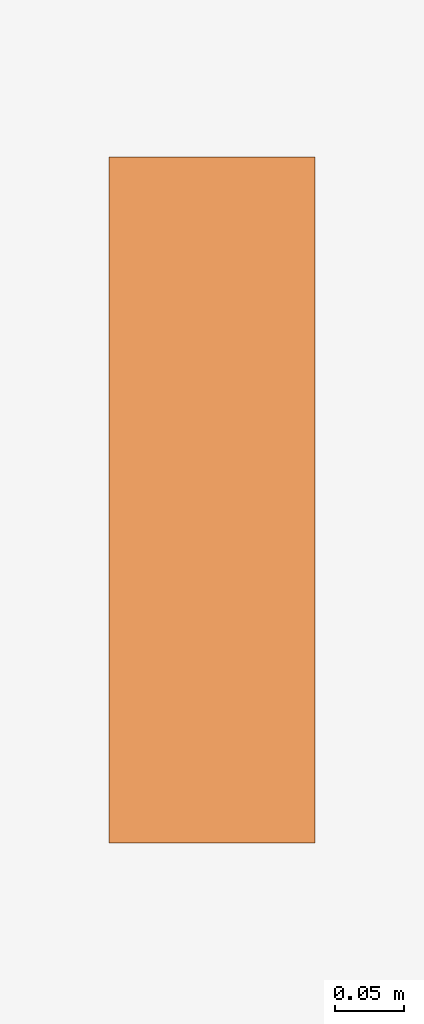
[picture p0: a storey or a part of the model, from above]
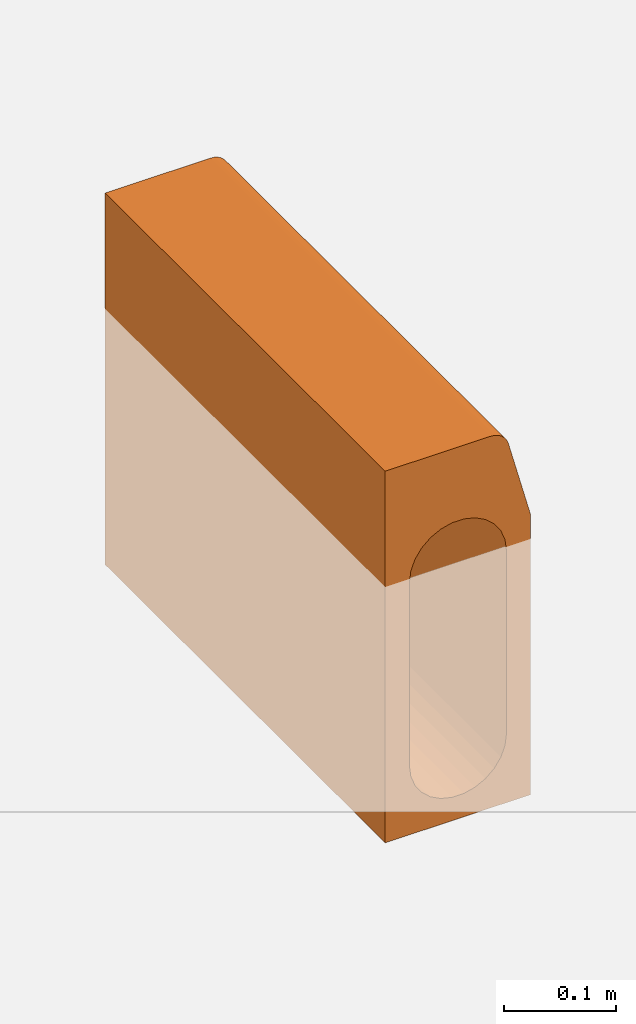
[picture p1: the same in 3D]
Properties of the parts of a building model (IFC2X3)

# File
Description: ViewDefinition [CoordinationView]
File name: 4230 - Blind unit - 500mm LG.ifc
Time: 2013-09-02T12:39:14
Written by: Autodesk Revit 2013
Made in: 20120221_2030(x64)

# IfcProject, Project Number
LongName: Project Name; Phase: Project Status

# IfcSite, Default
RefLatitude: 42, 21, 30, 344238; RefLongitude: -71, -3, -35, -194702; RefElevation: 0 mm

# IfcBuilding
Pset_BuildingCommon - NumberOfStoreys: 1
Other - Project Issue Date: Issue Date; Project Status: Project Status; Project Number: Project Number; Project Name: Project Name; Project Address: ## Street City, State Zip; Client Name: Owner

# IfcBuildingStorey, Level 1
LongName: Level 1; Elevation: 0 mm
Constraints - Elevation Base: 0; Elevation: 0 mm
Graphics - Line Pattern: Center; Symbol: M_Level Head - Circle: M_Level Head - Circle; Symbol at End 1 Default: no; Symbol at End 2 Default: yes; Color: 0; Line Weight: 1
Identity Data - Name: Level 1; Structural: no; Building Story: yes
Dimensions - Computation Height: 0 mm

# IfcBuildingElementProxy: 4230 - Blind unit - 500mm LG, Civil-Drainage-Channel-ACO-KerbDrain-HB405:4230 - Blind unit - 500mm LG:4230 - Blind unit - 500mm LG:312781
In: Level 1
Material: ACO Polymer Concrete.
Phasing - Phase Created: New Construction
Dimensions - Volume: 15757939 mm3; Void Depth: -280 mm; Void Length: 500 mm; Circular Void Depth: 2000 mm; Void Width: 150 mm
Constraints - Level: Level: Level 1; Moves With Nearby Elements: no
Pset_BuildingElementProxyCommon - Reference: 4230 - Blind unit - 500mm LG
Data - Drainage Slot Intake area: N/A; Product Standard: BS EN 1433:2002, CE marked, Kitemarked; Concrete Surround Volume - Load Class A 15 - D 400 - Concrete Pavement: 0.17m³/m; Channel C.S.A: 0.03m²; Drainage Slot Width: N/A; Concrete Surround Volume - Load Class A 15 - D 400 - Grass or Asphalt Pavement: 0.16m³/m; Load Class: A 15 - D 400; Installation - Concrete Grade: Refer to brochure; Hydraulic Performance: http://www.aco.co.uk/download.php?id=120; ACO Hydraulic Design Software: http://www.acodesign.co.uk; Connection Pipe O.D: N/A; Invert Depth: 380mm; Product Weight: 32 kg; Product Dimensions: 500mm x 150mm x 405mm (LxWxH)
Other - Revision: 1; CreatedBy: www.aco.co.uk
Green Building Properties - End Cap Recyclable: N/A; Channel Recycled Material Content: 20% minimum; End Cap Recycled Material Content: N/A; Access Cover/Frame Recycled Material Content: N/A; Access Cover/Frame Recyclable: N/A; Channel Recyclable: Fully recyclable
Construction - HB405 500_blindunit: yes; LH drop kerb: no; HB405 - 500: no; Closing end cap: no; Centre Stone: no; HB405 - 1000: no; LH inlet/outlet end cap: no; Access Unit: no; RH inlet/outlet end cap: no; RH drop kerb: no
Identity Data - Product Page URL: http://www.aco.co.uk/product_detail.php?id=3; Address: ACO Business Park, Hitchin Road, Shefford, Bedfordshire, United Kingdom SG17 5TE; URL: www.aco.co.uk; Product Code: 4230; e-mail Technical: technical@aco.co.uk; Cost: 0; Model: ACO KerbDrain HB405; Assembly Description: Rain Water Drainage; Assembly Code: D2040; Model Description: Combined kerb and drainage system; OmniClass Number: 23.70.50.24; Type Comments: ACO KerbDrain HB405 half battered blind kerb unit 500mm long; Telephone: +44 (0)1462 816666; Manufacturer: ACO Technologies plc - ACO Water Management Division; Maintenance guidelines: http://www.aco.co.uk/download.php?id=120; e-mail Sales: customersupport@aco.co.uk; OmniClass Title: Rainwater Removal; Installation guidelines: http://www.aco.co.uk/download.php?id=120; Product brochure: http://www.aco.co.uk/download.php?id=120; Price: POA - contact ACO; Fax: +44 (0)1462 815895
Materials and Finishes - End Cap Material: N/A; Connection Pipe Material Colour: N/A; Access Cover/Frame Colour: N/A; Access Cover/Frame Material: N/A; Channel Material: Vienite® Synthetic Resin Concrete; End Cap Colour: N/A; Access Cover/Frame Finish: N/A; Connection Pipe Material: N/A; Channel Colour: Grey
General - TagNumber: 0.000000; SerialNumber: 0.000000

# IfcOpeningElement: Recess (2)
In: Level 1
Constraints - Related to Mass: no; Level: Level: Level 1; Height Offset From Level: 0 mm; Room Bounding: yes
Structural - Enable Analytical Model: no; Structural: no
Phasing - Phase Created: New Construction
Dimensions - Thickness: 400 mm; Area: 151470000 mm2; Volume: 60567000000 mm3; Perimeter: 51360 mm
Analytical Properties - Roughness: 1; Absorptance: 0.1
Graphics - Coarse Scale Fill Color: 0
Construction - Default Thickness: 400 mm; Function: 0
Materials and Finishes - Structural Material: Plant

# IfcSlab: Floor:Generic Floor - 400mm, Floor:Generic Floor - 400mm:193825
In: Level 1
PredefinedType: FLOOR; Material: Plant 400 mm
Constraints - Related to Mass: no; Level: Level: Level 1; Height Offset From Level: 0 mm; Room Bounding: yes
Structural - Enable Analytical Model: no; Structural: no
Phasing - Phase Created: New Construction
Dimensions - Thickness: 400 mm; Area: 151470000 mm2; Volume: 60567000000 mm3; Perimeter: 51360 mm
Pset_SlabCommon - Reference: Generic Floor - 400mm; IsExternal: no; LoadBearing: yes
Analytical Properties - Roughness: 1; Absorptance: 0.1
Graphics - Coarse Scale Fill Color: 0
Construction - Default Thickness: 400 mm; Function: 0
Materials and Finishes - Structural Material: Plant
